VERSION 5.7 ;
BUSBITCHARS "[]" ;
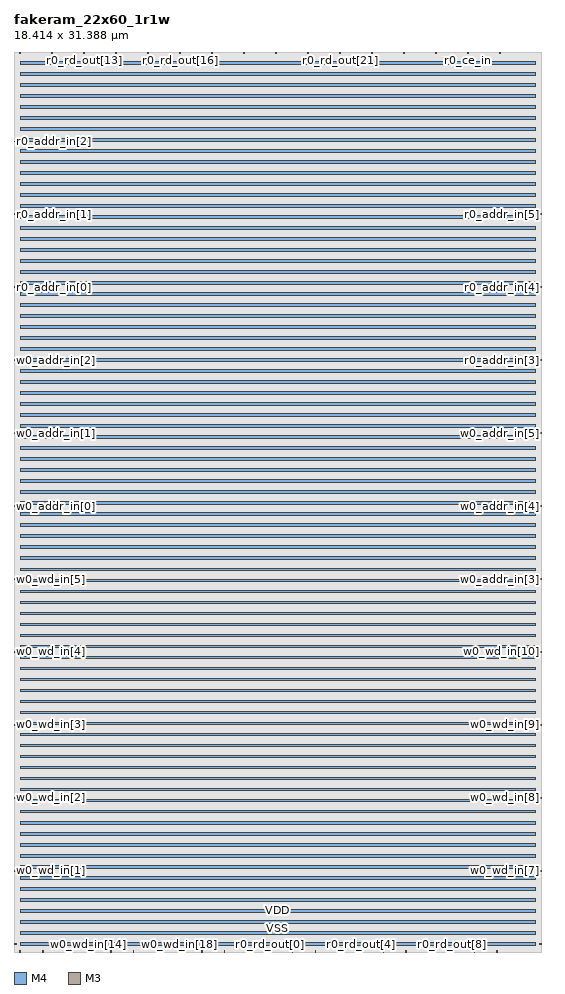
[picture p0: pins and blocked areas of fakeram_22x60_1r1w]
MACRO fakeram_22x60_1r1w
  FOREIGN fakeram_22x60_1r1w 0 0 ;
  SYMMETRY X Y R90 ;
  SIZE 18.414 BY 31.388 ;
  CLASS BLOCK ;
  PIN w0_wd_in[0]
    DIRECTION INPUT ;
    USE SIGNAL ;
    SHAPE ABUTMENT ;
    PORT
      LAYER M4 ;
      RECT 0.000 0.276 0.072 0.300 ;
    END
  END w0_wd_in[0]
  PIN w0_wd_in[1]
    DIRECTION INPUT ;
    USE SIGNAL ;
    SHAPE ABUTMENT ;
    PORT
      LAYER M4 ;
      RECT 0.000 2.820 0.072 2.844 ;
    END
  END w0_wd_in[1]
  PIN w0_wd_in[2]
    DIRECTION INPUT ;
    USE SIGNAL ;
    SHAPE ABUTMENT ;
    PORT
      LAYER M4 ;
      RECT 0.000 5.364 0.072 5.388 ;
    END
  END w0_wd_in[2]
  PIN w0_wd_in[3]
    DIRECTION INPUT ;
    USE SIGNAL ;
    SHAPE ABUTMENT ;
    PORT
      LAYER M4 ;
      RECT 0.000 7.908 0.072 7.932 ;
    END
  END w0_wd_in[3]
  PIN w0_wd_in[4]
    DIRECTION INPUT ;
    USE SIGNAL ;
    SHAPE ABUTMENT ;
    PORT
      LAYER M4 ;
      RECT 0.000 10.452 0.072 10.476 ;
    END
  END w0_wd_in[4]
  PIN w0_wd_in[5]
    DIRECTION INPUT ;
    USE SIGNAL ;
    SHAPE ABUTMENT ;
    PORT
      LAYER M4 ;
      RECT 0.000 12.996 0.072 13.020 ;
    END
  END w0_wd_in[5]
  PIN w0_wd_in[6]
    DIRECTION INPUT ;
    USE SIGNAL ;
    SHAPE ABUTMENT ;
    PORT
      LAYER M4 ;
      RECT 18.342 0.276 18.414 0.300 ;
    END
  END w0_wd_in[6]
  PIN w0_wd_in[7]
    DIRECTION INPUT ;
    USE SIGNAL ;
    SHAPE ABUTMENT ;
    PORT
      LAYER M4 ;
      RECT 18.342 2.820 18.414 2.844 ;
    END
  END w0_wd_in[7]
  PIN w0_wd_in[8]
    DIRECTION INPUT ;
    USE SIGNAL ;
    SHAPE ABUTMENT ;
    PORT
      LAYER M4 ;
      RECT 18.342 5.364 18.414 5.388 ;
    END
  END w0_wd_in[8]
  PIN w0_wd_in[9]
    DIRECTION INPUT ;
    USE SIGNAL ;
    SHAPE ABUTMENT ;
    PORT
      LAYER M4 ;
      RECT 18.342 7.908 18.414 7.932 ;
    END
  END w0_wd_in[9]
  PIN w0_wd_in[10]
    DIRECTION INPUT ;
    USE SIGNAL ;
    SHAPE ABUTMENT ;
    PORT
      LAYER M4 ;
      RECT 18.342 10.452 18.414 10.476 ;
    END
  END w0_wd_in[10]
  PIN w0_wd_in[11]
    DIRECTION INPUT ;
    USE SIGNAL ;
    SHAPE ABUTMENT ;
    PORT
      LAYER M3 ;
      RECT 0.207 0.000 0.225 0.054 ;
    END
  END w0_wd_in[11]
  PIN w0_wd_in[12]
    DIRECTION INPUT ;
    USE SIGNAL ;
    SHAPE ABUTMENT ;
    PORT
      LAYER M3 ;
      RECT 0.999 0.000 1.017 0.054 ;
    END
  END w0_wd_in[12]
  PIN w0_wd_in[13]
    DIRECTION INPUT ;
    USE SIGNAL ;
    SHAPE ABUTMENT ;
    PORT
      LAYER M3 ;
      RECT 1.791 0.000 1.809 0.054 ;
    END
  END w0_wd_in[13]
  PIN w0_wd_in[14]
    DIRECTION INPUT ;
    USE SIGNAL ;
    SHAPE ABUTMENT ;
    PORT
      LAYER M3 ;
      RECT 2.583 0.000 2.601 0.054 ;
    END
  END w0_wd_in[14]
  PIN w0_wd_in[15]
    DIRECTION INPUT ;
    USE SIGNAL ;
    SHAPE ABUTMENT ;
    PORT
      LAYER M3 ;
      RECT 3.375 0.000 3.393 0.054 ;
    END
  END w0_wd_in[15]
  PIN w0_wd_in[16]
    DIRECTION INPUT ;
    USE SIGNAL ;
    SHAPE ABUTMENT ;
    PORT
      LAYER M3 ;
      RECT 4.167 0.000 4.185 0.054 ;
    END
  END w0_wd_in[16]
  PIN w0_wd_in[17]
    DIRECTION INPUT ;
    USE SIGNAL ;
    SHAPE ABUTMENT ;
    PORT
      LAYER M3 ;
      RECT 4.959 0.000 4.977 0.054 ;
    END
  END w0_wd_in[17]
  PIN w0_wd_in[18]
    DIRECTION INPUT ;
    USE SIGNAL ;
    SHAPE ABUTMENT ;
    PORT
      LAYER M3 ;
      RECT 5.751 0.000 5.769 0.054 ;
    END
  END w0_wd_in[18]
  PIN w0_wd_in[19]
    DIRECTION INPUT ;
    USE SIGNAL ;
    SHAPE ABUTMENT ;
    PORT
      LAYER M3 ;
      RECT 6.543 0.000 6.561 0.054 ;
    END
  END w0_wd_in[19]
  PIN w0_wd_in[20]
    DIRECTION INPUT ;
    USE SIGNAL ;
    SHAPE ABUTMENT ;
    PORT
      LAYER M3 ;
      RECT 7.335 0.000 7.353 0.054 ;
    END
  END w0_wd_in[20]
  PIN w0_wd_in[21]
    DIRECTION INPUT ;
    USE SIGNAL ;
    SHAPE ABUTMENT ;
    PORT
      LAYER M3 ;
      RECT 8.127 0.000 8.145 0.054 ;
    END
  END w0_wd_in[21]
  PIN r0_rd_out[0]
    DIRECTION OUTPUT ;
    USE SIGNAL ;
    SHAPE ABUTMENT ;
    PORT
      LAYER M3 ;
      RECT 8.919 0.000 8.937 0.054 ;
    END
  END r0_rd_out[0]
  PIN r0_rd_out[1]
    DIRECTION OUTPUT ;
    USE SIGNAL ;
    SHAPE ABUTMENT ;
    PORT
      LAYER M3 ;
      RECT 9.711 0.000 9.729 0.054 ;
    END
  END r0_rd_out[1]
  PIN r0_rd_out[2]
    DIRECTION OUTPUT ;
    USE SIGNAL ;
    SHAPE ABUTMENT ;
    PORT
      LAYER M3 ;
      RECT 10.503 0.000 10.521 0.054 ;
    END
  END r0_rd_out[2]
  PIN r0_rd_out[3]
    DIRECTION OUTPUT ;
    USE SIGNAL ;
    SHAPE ABUTMENT ;
    PORT
      LAYER M3 ;
      RECT 11.295 0.000 11.313 0.054 ;
    END
  END r0_rd_out[3]
  PIN r0_rd_out[4]
    DIRECTION OUTPUT ;
    USE SIGNAL ;
    SHAPE ABUTMENT ;
    PORT
      LAYER M3 ;
      RECT 12.087 0.000 12.105 0.054 ;
    END
  END r0_rd_out[4]
  PIN r0_rd_out[5]
    DIRECTION OUTPUT ;
    USE SIGNAL ;
    SHAPE ABUTMENT ;
    PORT
      LAYER M3 ;
      RECT 12.879 0.000 12.897 0.054 ;
    END
  END r0_rd_out[5]
  PIN r0_rd_out[6]
    DIRECTION OUTPUT ;
    USE SIGNAL ;
    SHAPE ABUTMENT ;
    PORT
      LAYER M3 ;
      RECT 13.671 0.000 13.689 0.054 ;
    END
  END r0_rd_out[6]
  PIN r0_rd_out[7]
    DIRECTION OUTPUT ;
    USE SIGNAL ;
    SHAPE ABUTMENT ;
    PORT
      LAYER M3 ;
      RECT 14.463 0.000 14.481 0.054 ;
    END
  END r0_rd_out[7]
  PIN r0_rd_out[8]
    DIRECTION OUTPUT ;
    USE SIGNAL ;
    SHAPE ABUTMENT ;
    PORT
      LAYER M3 ;
      RECT 15.255 0.000 15.273 0.054 ;
    END
  END r0_rd_out[8]
  PIN r0_rd_out[9]
    DIRECTION OUTPUT ;
    USE SIGNAL ;
    SHAPE ABUTMENT ;
    PORT
      LAYER M3 ;
      RECT 16.047 0.000 16.065 0.054 ;
    END
  END r0_rd_out[9]
  PIN r0_rd_out[10]
    DIRECTION OUTPUT ;
    USE SIGNAL ;
    SHAPE ABUTMENT ;
    PORT
      LAYER M3 ;
      RECT 16.839 0.000 16.857 0.054 ;
    END
  END r0_rd_out[10]
  PIN r0_rd_out[11]
    DIRECTION OUTPUT ;
    USE SIGNAL ;
    SHAPE ABUTMENT ;
    PORT
      LAYER M3 ;
      RECT 0.207 31.334 0.225 31.388 ;
    END
  END r0_rd_out[11]
  PIN r0_rd_out[12]
    DIRECTION OUTPUT ;
    USE SIGNAL ;
    SHAPE ABUTMENT ;
    PORT
      LAYER M3 ;
      RECT 1.323 31.334 1.341 31.388 ;
    END
  END r0_rd_out[12]
  PIN r0_rd_out[13]
    DIRECTION OUTPUT ;
    USE SIGNAL ;
    SHAPE ABUTMENT ;
    PORT
      LAYER M3 ;
      RECT 2.439 31.334 2.457 31.388 ;
    END
  END r0_rd_out[13]
  PIN r0_rd_out[14]
    DIRECTION OUTPUT ;
    USE SIGNAL ;
    SHAPE ABUTMENT ;
    PORT
      LAYER M3 ;
      RECT 3.555 31.334 3.573 31.388 ;
    END
  END r0_rd_out[14]
  PIN r0_rd_out[15]
    DIRECTION OUTPUT ;
    USE SIGNAL ;
    SHAPE ABUTMENT ;
    PORT
      LAYER M3 ;
      RECT 4.671 31.334 4.689 31.388 ;
    END
  END r0_rd_out[15]
  PIN r0_rd_out[16]
    DIRECTION OUTPUT ;
    USE SIGNAL ;
    SHAPE ABUTMENT ;
    PORT
      LAYER M3 ;
      RECT 5.787 31.334 5.805 31.388 ;
    END
  END r0_rd_out[16]
  PIN r0_rd_out[17]
    DIRECTION OUTPUT ;
    USE SIGNAL ;
    SHAPE ABUTMENT ;
    PORT
      LAYER M3 ;
      RECT 6.903 31.334 6.921 31.388 ;
    END
  END r0_rd_out[17]
  PIN r0_rd_out[18]
    DIRECTION OUTPUT ;
    USE SIGNAL ;
    SHAPE ABUTMENT ;
    PORT
      LAYER M3 ;
      RECT 8.019 31.334 8.037 31.388 ;
    END
  END r0_rd_out[18]
  PIN r0_rd_out[19]
    DIRECTION OUTPUT ;
    USE SIGNAL ;
    SHAPE ABUTMENT ;
    PORT
      LAYER M3 ;
      RECT 9.135 31.334 9.153 31.388 ;
    END
  END r0_rd_out[19]
  PIN r0_rd_out[20]
    DIRECTION OUTPUT ;
    USE SIGNAL ;
    SHAPE ABUTMENT ;
    PORT
      LAYER M3 ;
      RECT 10.251 31.334 10.269 31.388 ;
    END
  END r0_rd_out[20]
  PIN r0_rd_out[21]
    DIRECTION OUTPUT ;
    USE SIGNAL ;
    SHAPE ABUTMENT ;
    PORT
      LAYER M3 ;
      RECT 11.367 31.334 11.385 31.388 ;
    END
  END r0_rd_out[21]
  PIN w0_addr_in[0]
    DIRECTION INPUT ;
    USE SIGNAL ;
    SHAPE ABUTMENT ;
    PORT
      LAYER M4 ;
      RECT 0.000 15.540 0.072 15.564 ;
    END
  END w0_addr_in[0]
  PIN w0_addr_in[1]
    DIRECTION INPUT ;
    USE SIGNAL ;
    SHAPE ABUTMENT ;
    PORT
      LAYER M4 ;
      RECT 0.000 18.084 0.072 18.108 ;
    END
  END w0_addr_in[1]
  PIN w0_addr_in[2]
    DIRECTION INPUT ;
    USE SIGNAL ;
    SHAPE ABUTMENT ;
    PORT
      LAYER M4 ;
      RECT 0.000 20.628 0.072 20.652 ;
    END
  END w0_addr_in[2]
  PIN w0_addr_in[3]
    DIRECTION INPUT ;
    USE SIGNAL ;
    SHAPE ABUTMENT ;
    PORT
      LAYER M4 ;
      RECT 18.342 12.996 18.414 13.020 ;
    END
  END w0_addr_in[3]
  PIN w0_addr_in[4]
    DIRECTION INPUT ;
    USE SIGNAL ;
    SHAPE ABUTMENT ;
    PORT
      LAYER M4 ;
      RECT 18.342 15.540 18.414 15.564 ;
    END
  END w0_addr_in[4]
  PIN w0_addr_in[5]
    DIRECTION INPUT ;
    USE SIGNAL ;
    SHAPE ABUTMENT ;
    PORT
      LAYER M4 ;
      RECT 18.342 18.084 18.414 18.108 ;
    END
  END w0_addr_in[5]
  PIN r0_addr_in[0]
    DIRECTION INPUT ;
    USE SIGNAL ;
    SHAPE ABUTMENT ;
    PORT
      LAYER M4 ;
      RECT 0.000 23.172 0.072 23.196 ;
    END
  END r0_addr_in[0]
  PIN r0_addr_in[1]
    DIRECTION INPUT ;
    USE SIGNAL ;
    SHAPE ABUTMENT ;
    PORT
      LAYER M4 ;
      RECT 0.000 25.716 0.072 25.740 ;
    END
  END r0_addr_in[1]
  PIN r0_addr_in[2]
    DIRECTION INPUT ;
    USE SIGNAL ;
    SHAPE ABUTMENT ;
    PORT
      LAYER M4 ;
      RECT 0.000 28.260 0.072 28.284 ;
    END
  END r0_addr_in[2]
  PIN r0_addr_in[3]
    DIRECTION INPUT ;
    USE SIGNAL ;
    SHAPE ABUTMENT ;
    PORT
      LAYER M4 ;
      RECT 18.342 20.628 18.414 20.652 ;
    END
  END r0_addr_in[3]
  PIN r0_addr_in[4]
    DIRECTION INPUT ;
    USE SIGNAL ;
    SHAPE ABUTMENT ;
    PORT
      LAYER M4 ;
      RECT 18.342 23.172 18.414 23.196 ;
    END
  END r0_addr_in[4]
  PIN r0_addr_in[5]
    DIRECTION INPUT ;
    USE SIGNAL ;
    SHAPE ABUTMENT ;
    PORT
      LAYER M4 ;
      RECT 18.342 25.716 18.414 25.740 ;
    END
  END r0_addr_in[5]
  PIN w0_we_in
    DIRECTION INPUT ;
    USE SIGNAL ;
    SHAPE ABUTMENT ;
    PORT
      LAYER M3 ;
      RECT 12.483 31.334 12.501 31.388 ;
    END
  END w0_we_in
  PIN w0_ce_in
    DIRECTION INPUT ;
    USE SIGNAL ;
    SHAPE ABUTMENT ;
    PORT
      LAYER M3 ;
      RECT 13.599 31.334 13.617 31.388 ;
    END
  END w0_ce_in
  PIN w0_clk
    DIRECTION INPUT ;
    USE SIGNAL ;
    SHAPE ABUTMENT ;
    PORT
      LAYER M3 ;
      RECT 14.715 31.334 14.733 31.388 ;
    END
  END w0_clk
  PIN r0_ce_in
    DIRECTION INPUT ;
    USE SIGNAL ;
    SHAPE ABUTMENT ;
    PORT
      LAYER M3 ;
      RECT 15.831 31.334 15.849 31.388 ;
    END
  END r0_ce_in
  PIN r0_clk
    DIRECTION INPUT ;
    USE SIGNAL ;
    SHAPE ABUTMENT ;
    PORT
      LAYER M3 ;
      RECT 16.947 31.334 16.965 31.388 ;
    END
  END r0_clk
  PIN VSS
    DIRECTION INOUT ;
    USE GROUND ;
    PORT
      LAYER M4 ;
      RECT 0.216 0.240 18.198 0.336 ;
      RECT 0.216 1.008 18.198 1.104 ;
      RECT 0.216 1.776 18.198 1.872 ;
      RECT 0.216 2.544 18.198 2.640 ;
      RECT 0.216 3.312 18.198 3.408 ;
      RECT 0.216 4.080 18.198 4.176 ;
      RECT 0.216 4.848 18.198 4.944 ;
      RECT 0.216 5.616 18.198 5.712 ;
      RECT 0.216 6.384 18.198 6.480 ;
      RECT 0.216 7.152 18.198 7.248 ;
      RECT 0.216 7.920 18.198 8.016 ;
      RECT 0.216 8.688 18.198 8.784 ;
      RECT 0.216 9.456 18.198 9.552 ;
      RECT 0.216 10.224 18.198 10.320 ;
      RECT 0.216 10.992 18.198 11.088 ;
      RECT 0.216 11.760 18.198 11.856 ;
      RECT 0.216 12.528 18.198 12.624 ;
      RECT 0.216 13.296 18.198 13.392 ;
      RECT 0.216 14.064 18.198 14.160 ;
      RECT 0.216 14.832 18.198 14.928 ;
      RECT 0.216 15.600 18.198 15.696 ;
      RECT 0.216 16.368 18.198 16.464 ;
      RECT 0.216 17.136 18.198 17.232 ;
      RECT 0.216 17.904 18.198 18.000 ;
      RECT 0.216 18.672 18.198 18.768 ;
      RECT 0.216 19.440 18.198 19.536 ;
      RECT 0.216 20.208 18.198 20.304 ;
      RECT 0.216 20.976 18.198 21.072 ;
      RECT 0.216 21.744 18.198 21.840 ;
      RECT 0.216 22.512 18.198 22.608 ;
      RECT 0.216 23.280 18.198 23.376 ;
      RECT 0.216 24.048 18.198 24.144 ;
      RECT 0.216 24.816 18.198 24.912 ;
      RECT 0.216 25.584 18.198 25.680 ;
      RECT 0.216 26.352 18.198 26.448 ;
      RECT 0.216 27.120 18.198 27.216 ;
      RECT 0.216 27.888 18.198 27.984 ;
      RECT 0.216 28.656 18.198 28.752 ;
      RECT 0.216 29.424 18.198 29.520 ;
      RECT 0.216 30.192 18.198 30.288 ;
      RECT 0.216 30.960 18.198 31.056 ;
    END
  END VSS
  PIN VDD
    DIRECTION INOUT ;
    USE POWER ;
    PORT
      LAYER M4 ;
      RECT 0.216 0.624 18.198 0.720 ;
      RECT 0.216 1.392 18.198 1.488 ;
      RECT 0.216 2.160 18.198 2.256 ;
      RECT 0.216 2.928 18.198 3.024 ;
      RECT 0.216 3.696 18.198 3.792 ;
      RECT 0.216 4.464 18.198 4.560 ;
      RECT 0.216 5.232 18.198 5.328 ;
      RECT 0.216 6.000 18.198 6.096 ;
      RECT 0.216 6.768 18.198 6.864 ;
      RECT 0.216 7.536 18.198 7.632 ;
      RECT 0.216 8.304 18.198 8.400 ;
      RECT 0.216 9.072 18.198 9.168 ;
      RECT 0.216 9.840 18.198 9.936 ;
      RECT 0.216 10.608 18.198 10.704 ;
      RECT 0.216 11.376 18.198 11.472 ;
      RECT 0.216 12.144 18.198 12.240 ;
      RECT 0.216 12.912 18.198 13.008 ;
      RECT 0.216 13.680 18.198 13.776 ;
      RECT 0.216 14.448 18.198 14.544 ;
      RECT 0.216 15.216 18.198 15.312 ;
      RECT 0.216 15.984 18.198 16.080 ;
      RECT 0.216 16.752 18.198 16.848 ;
      RECT 0.216 17.520 18.198 17.616 ;
      RECT 0.216 18.288 18.198 18.384 ;
      RECT 0.216 19.056 18.198 19.152 ;
      RECT 0.216 19.824 18.198 19.920 ;
      RECT 0.216 20.592 18.198 20.688 ;
      RECT 0.216 21.360 18.198 21.456 ;
      RECT 0.216 22.128 18.198 22.224 ;
      RECT 0.216 22.896 18.198 22.992 ;
      RECT 0.216 23.664 18.198 23.760 ;
      RECT 0.216 24.432 18.198 24.528 ;
      RECT 0.216 25.200 18.198 25.296 ;
      RECT 0.216 25.968 18.198 26.064 ;
      RECT 0.216 26.736 18.198 26.832 ;
      RECT 0.216 27.504 18.198 27.600 ;
      RECT 0.216 28.272 18.198 28.368 ;
      RECT 0.216 29.040 18.198 29.136 ;
      RECT 0.216 29.808 18.198 29.904 ;
      RECT 0.216 30.576 18.198 30.672 ;
    END
  END VDD
  OBS
    LAYER M1 ;
    RECT 0 0 18.414 31.388 ;
    LAYER M2 ;
    RECT 0 0 18.414 31.388 ;
    LAYER M3 ;
    RECT 0 0 18.414 31.388 ;
    LAYER M4 ;
    RECT 0 0 18.414 31.388 ;
  END
END fakeram_22x60_1r1w

END LIBRARY
